# LEF of the project cell library pl018 (generated by step5_library/gen_library.py)
# Technology section copied from Qflow tech/osu018/osu018_stdcells.lef (layers, vias, via rules).
# The project library adds its own placement site and cell macros (step5_library/gen_library.py).
VERSION 5.4 ;
NAMESCASESENSITIVE ON ;
BUSBITCHARS "[]" ;
DIVIDERCHAR "/" ;
UNITS
  DATABASE MICRONS 1000 ;
END UNITS

USEMINSPACING OBS ON ;
USEMINSPACING PIN OFF ;
CLEARANCEMEASURE EUCLIDEAN ;


MANUFACTURINGGRID 0.05 ;

LAYER nwell
  TYPE	MASTERSLICE ;
END nwell

LAYER nactive
  TYPE	MASTERSLICE ;
END nactive

LAYER pactive
  TYPE	MASTERSLICE ;
END pactive

LAYER poly
  TYPE	MASTERSLICE ;
END poly

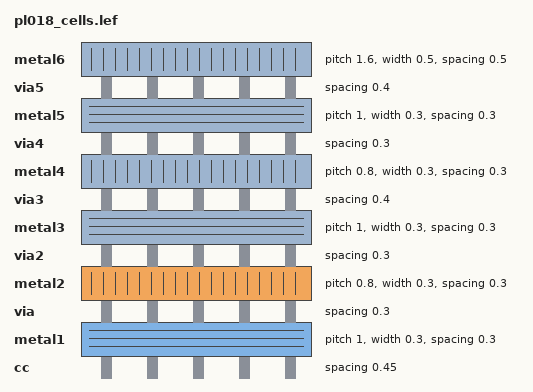
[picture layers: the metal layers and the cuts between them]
LAYER cc
  TYPE	CUT ;
  SPACING	0.45 ;
END cc

LAYER metal1
  TYPE		ROUTING ;
  DIRECTION	HORIZONTAL ;
  PITCH		1  ;
  OFFSET	0.5 ;
  WIDTH		0.3 ;
  SPACING	0.3 ;
  RESISTANCE	RPERSQ 0.08 ;
  CAPACITANCE	CPERSQDIST 3.8e-05 ;
  EDGECAPACITANCE 8.000000e-05 ;
END metal1

LAYER via
  TYPE	CUT ;
  SPACING	0.3 ;
END via

LAYER metal2
  TYPE		ROUTING ;
  DIRECTION	VERTICAL ;
  PITCH		0.8  ;
  OFFSET	0.4 ;
  WIDTH		0.3 ;
  SPACING	0.3 ;
  RESISTANCE	RPERSQ 0.08 ;
  CAPACITANCE	CPERSQDIST 1.9e-05 ;
  EDGECAPACITANCE 6.000000e-05 ;
END metal2

LAYER via2
  TYPE	CUT ;
  SPACING	0.3 ;
END via2

LAYER metal3
  TYPE		ROUTING ;
  DIRECTION	HORIZONTAL ;
  PITCH		1  ;
  OFFSET	0.5 ;
  WIDTH		0.3 ;
  SPACING	0.3 ;
  RESISTANCE	RPERSQ 0.08 ;
  CAPACITANCE	CPERSQDIST 1.3e-05 ;
  EDGECAPACITANCE 5.400000e-05 ;
END metal3

LAYER via3
  TYPE	CUT ;
  SPACING	0.4 ;
END via3

LAYER metal4
  TYPE		ROUTING ;
  DIRECTION	VERTICAL ;
  PITCH		0.8  ;
  OFFSET	0.4 ;
  WIDTH		0.3 ;
  SPACING	0.3 ;
  RESISTANCE	RPERSQ 0.07 ;
  CAPACITANCE	CPERSQDIST 8e-06 ;
  EDGECAPACITANCE 4.100000e-05 ;
END metal4

LAYER via4
  TYPE	CUT ;
  SPACING	0.3 ;
END via4

LAYER metal5
  TYPE		ROUTING ;
  DIRECTION	HORIZONTAL ;
  PITCH		1  ;
  OFFSET	0.5 ;
  WIDTH		0.3 ;
  SPACING	0.3 ;
  RESISTANCE	RPERSQ 0.07 ;
  CAPACITANCE	CPERSQDIST 8e-06 ;
  EDGECAPACITANCE 2.400000e-05 ;
END metal5

LAYER via5
  TYPE	CUT ;
  SPACING	0.4 ;
END via5

LAYER metal6
  TYPE		ROUTING ;
  DIRECTION	VERTICAL ;
  PITCH		1.6  ;
  OFFSET	0.8 ;
  WIDTH		0.5 ;
  SPACING	0.5 ;
  RESISTANCE	RPERSQ 0.03 ;
  CAPACITANCE	CPERSQDIST 3e-06 ;
  EDGECAPACITANCE 2.000000e-05 ;
END metal6

VIA M2_M1 DEFAULT
  LAYER metal1 ;
    RECT -0.200 -0.200 0.200 0.200 ;
  LAYER via ;
    RECT -0.100 -0.100 0.100 0.100 ;
  LAYER metal2 ;
    RECT -0.200 -0.200 0.200 0.200 ;
END M2_M1

VIA M3_M2 DEFAULT
  LAYER metal2 ;
    RECT -0.200 -0.200 0.200 0.200 ;
  LAYER via2 ;
    RECT -0.100 -0.100 0.100 0.100 ;
  LAYER metal3 ;
    RECT -0.200 -0.200 0.200 0.200 ;
END M3_M2

VIA M4_M3 DEFAULT
  LAYER metal3 ;
    RECT -0.200 -0.200 0.200 0.200 ;
  LAYER via3 ;
    RECT -0.100 -0.100 0.100 0.100 ;
  LAYER metal4 ;
    RECT -0.200 -0.200 0.200 0.200 ;
END M4_M3

VIA M5_M4 DEFAULT
  LAYER metal4 ;
    RECT -0.200 -0.200 0.200 0.200 ;
  LAYER via4 ;
    RECT -0.100 -0.100 0.100 0.100 ;
  LAYER metal5 ;
    RECT -0.200 -0.200 0.200 0.200 ;
END M5_M4

VIA M6_M5 DEFAULT
  LAYER metal5 ;
    RECT -0.25 -0.25 0.25 0.25 ;
  LAYER via5 ;
    RECT -0.15 -0.15 0.15 0.15 ;
  LAYER metal6 ;
    RECT -0.25 -0.25 0.25 0.25 ;
END M6_M5


VIARULE viagen21 GENERATE
  LAYER metal1 ;
    DIRECTION HORIZONTAL ;
    WIDTH 0.3 TO 60 ;
    OVERHANG 0.1 ;
    METALOVERHANG 0 ;
  LAYER metal2 ;
    DIRECTION VERTICAL ;
    WIDTH 0.3 TO 60 ;
    OVERHANG 0.1 ;
    METALOVERHANG 0 ;
  LAYER via ;
    RECT -0.1 -0.1 0.1 0.1 ;
    SPACING 0.5 BY 0.5 ;
END viagen21

VIARULE viagen32 GENERATE
  LAYER metal3 ;
    DIRECTION HORIZONTAL ;
    WIDTH 0.3 TO 60 ;
    OVERHANG 0.1 ;
    METALOVERHANG 0 ;
  LAYER metal2 ;
    DIRECTION VERTICAL ;
    WIDTH 0.3 TO 60 ;
    OVERHANG 0.1 ;
    METALOVERHANG 0 ;
  LAYER via2 ;
    RECT -0.1 -0.1 0.1 0.1 ;
    SPACING 0.5 BY 0.5 ;
END viagen32

VIARULE viagen43 GENERATE
  LAYER metal3 ;
    DIRECTION HORIZONTAL ;
    WIDTH 0.3 TO 60 ;
    OVERHANG 0.1 ;
    METALOVERHANG 0 ;
  LAYER metal4 ;
    DIRECTION VERTICAL ;
    WIDTH 0.3 TO 60 ;
    OVERHANG 0.1 ;
    METALOVERHANG 0 ;
  LAYER via3 ;
    RECT -0.1 -0.1 0.1 0.1 ;
    SPACING 0.6 BY 0.6 ;
END viagen43

VIARULE viagen54 GENERATE
  LAYER metal5 ;
    DIRECTION HORIZONTAL ;
    WIDTH 0.3 TO 60 ;
    OVERHANG 0.1 ;
    METALOVERHANG 0 ;
  LAYER metal4 ;
    DIRECTION VERTICAL ;
    WIDTH 0.3 TO 60 ;
    OVERHANG 0.1 ;
    METALOVERHANG 0 ;
  LAYER via4 ;
    RECT -0.1 -0.1 0.1 0.1 ;
    SPACING 0.5 BY 0.5 ;
END viagen54

VIARULE viagen65 GENERATE
  LAYER metal5 ;
    DIRECTION HORIZONTAL ;
    WIDTH 0.5 TO 60 ;
    OVERHANG 0.1 ;
    METALOVERHANG 0 ;
  LAYER metal6 ;
    DIRECTION VERTICAL ;
    WIDTH 0.5 TO 60 ;
    OVERHANG 0.1 ;
    METALOVERHANG 0 ;
  LAYER via5 ;
    RECT -0.15 -0.15 0.15 0.15 ;
    SPACING 0.7 BY 0.7 ;
END viagen65

VIARULE TURN1 GENERATE
  LAYER metal1 ;
    DIRECTION HORIZONTAL ;
  LAYER metal1 ;
    DIRECTION VERTICAL ;
END TURN1

VIARULE TURN2 GENERATE
  LAYER metal2 ;
    DIRECTION HORIZONTAL ;
  LAYER metal2 ;
    DIRECTION VERTICAL ;
END TURN2

VIARULE TURN3 GENERATE
  LAYER metal3 ;
    DIRECTION HORIZONTAL ;
  LAYER metal3 ;
    DIRECTION VERTICAL ;
END TURN3

VIARULE TURN4 GENERATE
  LAYER metal4 ;
    DIRECTION HORIZONTAL ;
  LAYER metal4 ;
    DIRECTION VERTICAL ;
END TURN4

VIARULE TURN5 GENERATE
  LAYER metal5 ;
    DIRECTION HORIZONTAL ;
  LAYER metal5 ;
    DIRECTION VERTICAL ;
END TURN5

VIARULE TURN6 GENERATE
  LAYER metal6 ;
    DIRECTION HORIZONTAL ;
  LAYER metal6 ;
    DIRECTION VERTICAL ;
END TURN6


SITE  plcore
    CLASS	CORE ;
    SYMMETRY	Y ;
    SIZE	0.800 BY 8.000 ;
END  plcore

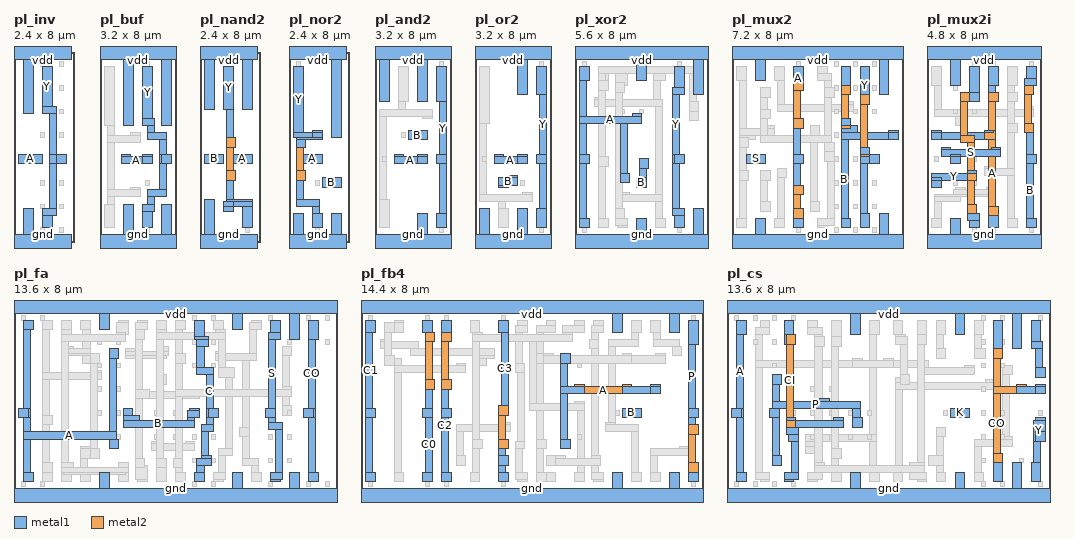
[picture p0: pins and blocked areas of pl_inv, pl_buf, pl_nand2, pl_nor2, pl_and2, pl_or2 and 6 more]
MACRO pl_inv
  CLASS CORE ;
  FOREIGN pl_inv 0.000 0.000 ;
  ORIGIN 0.000 0.000 ;
  SIZE 2.400 BY 8.000 ;
  SYMMETRY X Y ;
  SITE plcore ;
  PIN A
    DIRECTION INPUT ;
    PORT
      LAYER metal1 ;
        RECT 0.200 3.300 0.600 3.700 ;
        RECT 0.200 3.300 1.200 3.700 ;
    END
  END A
  PIN Y
    DIRECTION OUTPUT ;
    PORT
      LAYER metal1 ;
        RECT 1.800 3.300 2.200 3.700 ;
        RECT 1.200 0.600 1.600 1.100 ;
        RECT 1.200 1.100 1.800 1.400 ;
        RECT 1.500 1.400 1.800 3.300 ;
        RECT 1.500 3.300 2.200 3.700 ;
        RECT 1.500 3.700 1.800 5.400 ;
        RECT 1.200 5.400 1.800 5.700 ;
        RECT 1.200 5.700 1.600 7.400 ;
    END
  END Y
  PIN vdd
    DIRECTION INOUT ;
    USE POWER ;
    SHAPE ABUTMENT ;
    PORT
      LAYER metal1 ;
        RECT 0.400 5.400 0.800 7.700 ;
        RECT 0.000 7.700 2.400 8.300 ;
    END
  END vdd
  PIN gnd
    DIRECTION INOUT ;
    USE GROUND ;
    SHAPE ABUTMENT ;
    PORT
      LAYER metal1 ;
        RECT 0.000 -0.300 2.400 0.300 ;
        RECT 0.400 0.300 0.800 1.400 ;
    END
  END gnd
  OBS
    LAYER metal1 ;
      RECT 1.100 0.400 1.300 0.600 ;
      RECT 1.100 1.400 1.300 1.600 ;
      RECT 1.100 2.400 1.300 2.600 ;
      RECT 1.100 4.400 1.300 4.600 ;
      RECT 1.100 7.400 1.300 7.600 ;
      RECT 1.900 0.400 2.100 0.600 ;
      RECT 1.900 1.400 2.100 1.600 ;
      RECT 1.900 2.400 2.100 2.600 ;
      RECT 1.900 4.400 2.100 4.600 ;
      RECT 1.900 5.400 2.100 5.600 ;
      RECT 1.900 6.400 2.100 6.600 ;
      RECT 1.900 7.400 2.100 7.600 ;
  END
END pl_inv

MACRO pl_buf
  CLASS CORE ;
  FOREIGN pl_buf 0.000 0.000 ;
  ORIGIN 0.000 0.000 ;
  SIZE 3.200 BY 8.000 ;
  SYMMETRY X Y ;
  SITE plcore ;
  PIN A
    DIRECTION INPUT ;
    PORT
      LAYER metal1 ;
        RECT 1.800 3.300 2.200 3.700 ;
        RECT 0.900 3.300 2.200 3.600 ;
        RECT 0.900 3.600 1.300 3.700 ;
        RECT 1.800 3.600 2.200 3.700 ;
    END
  END A
  PIN Y
    DIRECTION OUTPUT ;
    PORT
      LAYER metal1 ;
        RECT 2.600 3.300 3.000 3.700 ;
        RECT 1.800 0.600 2.200 1.300 ;
        RECT 1.800 1.300 2.300 1.600 ;
        RECT 2.000 1.600 2.300 1.900 ;
        RECT 2.000 1.900 2.800 2.200 ;
        RECT 2.500 2.200 2.800 3.300 ;
        RECT 2.500 3.300 3.000 3.700 ;
        RECT 2.500 3.700 2.800 4.300 ;
        RECT 2.000 4.300 2.800 4.600 ;
        RECT 2.000 4.600 2.300 4.900 ;
        RECT 1.800 4.900 2.300 5.200 ;
        RECT 1.800 5.200 2.200 7.400 ;
    END
  END Y
  PIN vdd
    DIRECTION INOUT ;
    USE POWER ;
    SHAPE ABUTMENT ;
    PORT
      LAYER metal1 ;
        RECT 1.000 4.900 1.400 7.700 ;
        RECT 2.600 4.900 3.000 7.700 ;
        RECT 0.000 7.700 3.200 8.300 ;
    END
  END vdd
  PIN gnd
    DIRECTION INOUT ;
    USE GROUND ;
    SHAPE ABUTMENT ;
    PORT
      LAYER metal1 ;
        RECT 0.000 -0.300 3.200 0.300 ;
        RECT 1.000 0.300 1.400 1.600 ;
        RECT 2.600 0.300 3.000 1.600 ;
    END
  END gnd
  OBS
    LAYER metal1 ;
      RECT 0.200 0.600 0.600 1.600 ;
      RECT 0.300 1.600 0.600 1.900 ;
      RECT 0.300 1.900 1.700 2.200 ;
      RECT 0.300 2.200 0.600 4.200 ;
      RECT 1.300 2.200 1.700 2.300 ;
      RECT 0.300 4.200 1.700 4.500 ;
      RECT 0.300 4.500 0.600 4.900 ;
      RECT 1.300 4.500 1.700 4.600 ;
      RECT 0.200 4.900 0.600 7.400 ;
      RECT 1.900 0.400 2.100 0.600 ;
      RECT 1.900 2.400 2.100 2.600 ;
      RECT 1.900 7.400 2.100 7.600 ;
  END
END pl_buf

MACRO pl_nand2
  CLASS CORE ;
  FOREIGN pl_nand2 0.000 0.000 ;
  ORIGIN 0.000 0.000 ;
  SIZE 2.400 BY 8.000 ;
  SYMMETRY X Y ;
  SITE plcore ;
  PIN A
    DIRECTION INPUT ;
    PORT
      LAYER metal1 ;
        RECT 1.800 3.300 2.200 3.700 ;
        RECT 1.400 3.300 2.200 3.700 ;
    END
  END A
  PIN B
    DIRECTION INPUT ;
    PORT
      LAYER metal1 ;
        RECT 0.200 3.300 0.600 3.700 ;
        RECT 0.200 3.300 1.000 3.700 ;
    END
  END B
  PIN Y
    DIRECTION OUTPUT ;
    PORT
      LAYER metal1 ;
        RECT 1.000 1.300 1.400 1.700 ;
        RECT 1.800 0.600 2.200 1.500 ;
        RECT 1.000 1.300 1.400 1.500 ;
        RECT 1.000 1.500 2.200 1.700 ;
        RECT 1.100 1.700 2.200 1.800 ;
        RECT 1.100 1.800 1.400 2.600 ;
        RECT 1.100 2.600 1.500 3.000 ;
        RECT 1.100 4.000 1.500 4.400 ;
        RECT 1.100 4.400 1.400 5.600 ;
        RECT 1.000 5.600 1.400 7.400 ;
      LAYER metal2 ;
        RECT 1.100 2.600 1.500 3.000 ;
        RECT 1.100 3.000 1.400 4.000 ;
        RECT 1.100 4.000 1.500 4.400 ;
    END
  END Y
  PIN vdd
    DIRECTION INOUT ;
    USE POWER ;
    SHAPE ABUTMENT ;
    PORT
      LAYER metal1 ;
        RECT 0.200 5.600 0.600 7.700 ;
        RECT 1.800 5.600 2.200 7.700 ;
        RECT 0.000 7.700 2.400 8.300 ;
    END
  END vdd
  PIN gnd
    DIRECTION INOUT ;
    USE GROUND ;
    SHAPE ABUTMENT ;
    PORT
      LAYER metal1 ;
        RECT 0.000 -0.300 2.400 0.300 ;
        RECT 0.200 0.300 0.600 1.800 ;
    END
  END gnd
  OBS
    LAYER metal1 ;
      RECT 1.100 3.400 1.300 3.600 ;
      RECT 1.100 7.400 1.300 7.600 ;
      RECT 1.900 0.400 2.100 0.600 ;
  END
END pl_nand2

MACRO pl_nor2
  CLASS CORE ;
  FOREIGN pl_nor2 0.000 0.000 ;
  ORIGIN 0.000 0.000 ;
  SIZE 2.400 BY 8.000 ;
  SYMMETRY X Y ;
  SITE plcore ;
  PIN A
    DIRECTION INPUT ;
    PORT
      LAYER metal1 ;
        RECT 1.000 3.300 1.400 3.700 ;
        RECT 0.600 3.300 1.400 3.700 ;
    END
  END A
  PIN B
    DIRECTION INPUT ;
    PORT
      LAYER metal1 ;
        RECT 1.800 2.300 2.200 2.700 ;
        RECT 1.400 2.300 2.200 2.700 ;
    END
  END B
  PIN Y
    DIRECTION OUTPUT ;
    PORT
      LAYER metal1 ;
        RECT 1.000 4.300 1.400 4.700 ;
        RECT 1.000 0.600 1.400 1.200 ;
        RECT 1.000 1.200 1.300 1.500 ;
        RECT 0.300 1.500 1.300 1.800 ;
        RECT 0.300 1.800 0.600 2.600 ;
        RECT 0.300 2.600 0.700 3.000 ;
        RECT 0.300 4.000 0.700 4.300 ;
        RECT 0.300 4.300 1.400 4.400 ;
        RECT 0.200 4.400 1.400 4.600 ;
        RECT 0.200 4.600 0.600 7.400 ;
        RECT 1.000 4.600 1.400 4.700 ;
      LAYER metal2 ;
        RECT 0.300 2.600 0.700 3.000 ;
        RECT 0.300 3.000 0.600 4.000 ;
        RECT 0.300 4.000 0.700 4.400 ;
    END
  END Y
  PIN vdd
    DIRECTION INOUT ;
    USE POWER ;
    SHAPE ABUTMENT ;
    PORT
      LAYER metal1 ;
        RECT 1.800 4.400 2.200 7.700 ;
        RECT 0.000 7.700 2.400 8.300 ;
    END
  END vdd
  PIN gnd
    DIRECTION INOUT ;
    USE GROUND ;
    SHAPE ABUTMENT ;
    PORT
      LAYER metal1 ;
        RECT 0.000 -0.300 2.400 0.300 ;
        RECT 0.200 0.300 0.600 1.200 ;
        RECT 1.800 0.300 2.200 1.200 ;
    END
  END gnd
  OBS
    LAYER metal1 ;
      RECT 0.300 3.400 0.500 3.600 ;
      RECT 0.300 7.400 0.500 7.600 ;
      RECT 1.100 0.400 1.300 0.600 ;
      RECT 1.100 2.400 1.300 2.600 ;
    LAYER metal2 ;
      RECT 0.300 2.400 0.500 2.600 ;
      RECT 0.300 4.400 0.500 4.600 ;
  END
END pl_nor2

MACRO pl_and2
  CLASS CORE ;
  FOREIGN pl_and2 0.000 0.000 ;
  ORIGIN 0.000 0.000 ;
  SIZE 3.200 BY 8.000 ;
  SYMMETRY X Y ;
  SITE plcore ;
  PIN A
    DIRECTION INPUT ;
    PORT
      LAYER metal1 ;
        RECT 1.800 3.300 2.200 3.700 ;
        RECT 0.800 3.300 2.200 3.600 ;
        RECT 0.800 3.600 1.200 3.700 ;
        RECT 1.800 3.600 2.200 3.700 ;
    END
  END A
  PIN B
    DIRECTION INPUT ;
    PORT
      LAYER metal1 ;
        RECT 1.800 4.300 2.200 4.700 ;
        RECT 1.400 4.300 2.200 4.700 ;
    END
  END B
  PIN Y
    DIRECTION OUTPUT ;
    PORT
      LAYER metal1 ;
        RECT 2.600 3.300 3.000 3.700 ;
        RECT 2.600 0.600 3.000 1.200 ;
        RECT 2.700 1.200 3.000 3.300 ;
        RECT 2.600 3.300 3.000 3.700 ;
        RECT 2.700 3.700 3.000 5.900 ;
        RECT 2.600 5.900 3.000 7.400 ;
    END
  END Y
  PIN vdd
    DIRECTION INOUT ;
    USE POWER ;
    SHAPE ABUTMENT ;
    PORT
      LAYER metal1 ;
        RECT 0.200 5.900 0.600 7.700 ;
        RECT 1.800 5.900 2.200 7.700 ;
        RECT 0.000 7.700 3.200 8.300 ;
    END
  END vdd
  PIN gnd
    DIRECTION INOUT ;
    USE GROUND ;
    SHAPE ABUTMENT ;
    PORT
      LAYER metal1 ;
        RECT 0.000 -0.300 3.200 0.300 ;
        RECT 1.800 0.300 2.200 1.200 ;
    END
  END gnd
  OBS
    LAYER metal1 ;
      RECT 0.200 0.600 0.600 1.800 ;
      RECT 0.200 1.800 0.500 5.300 ;
      RECT 2.000 5.200 2.400 5.300 ;
      RECT 0.200 5.300 2.400 5.600 ;
      RECT 1.000 5.600 1.300 5.900 ;
      RECT 1.000 5.900 1.400 7.400 ;
      RECT 0.300 3.400 0.500 3.600 ;
      RECT 1.100 4.400 1.300 4.600 ;
      RECT 2.700 0.400 2.900 0.600 ;
      RECT 2.700 7.400 2.900 7.600 ;
  END
END pl_and2

MACRO pl_or2
  CLASS CORE ;
  FOREIGN pl_or2 0.000 0.000 ;
  ORIGIN 0.000 0.000 ;
  SIZE 3.200 BY 8.000 ;
  SYMMETRY X Y ;
  SITE plcore ;
  PIN A
    DIRECTION INPUT ;
    PORT
      LAYER metal1 ;
        RECT 1.800 3.300 2.200 3.700 ;
        RECT 0.800 3.300 2.200 3.600 ;
        RECT 0.800 3.600 1.200 3.700 ;
        RECT 1.800 3.600 2.200 3.700 ;
    END
  END A
  PIN B
    DIRECTION INPUT ;
    PORT
      LAYER metal1 ;
        RECT 1.000 2.300 1.400 2.700 ;
        RECT 1.000 2.300 1.400 2.400 ;
        RECT 1.000 2.400 1.800 2.700 ;
        RECT 1.400 2.700 1.800 2.800 ;
    END
  END B
  PIN Y
    DIRECTION OUTPUT ;
    PORT
      LAYER metal1 ;
        RECT 2.600 3.300 3.000 3.700 ;
        RECT 2.600 0.600 3.000 1.400 ;
        RECT 2.700 1.400 3.000 3.300 ;
        RECT 2.600 3.300 3.000 3.700 ;
        RECT 2.700 3.700 3.000 6.200 ;
        RECT 2.600 6.200 3.000 7.400 ;
    END
  END Y
  PIN vdd
    DIRECTION INOUT ;
    USE POWER ;
    SHAPE ABUTMENT ;
    PORT
      LAYER metal1 ;
        RECT 1.800 6.200 2.200 7.700 ;
        RECT 0.000 7.700 3.200 8.300 ;
    END
  END vdd
  PIN gnd
    DIRECTION INOUT ;
    USE GROUND ;
    SHAPE ABUTMENT ;
    PORT
      LAYER metal1 ;
        RECT 0.000 -0.300 3.200 0.300 ;
        RECT 0.200 0.300 0.600 1.400 ;
        RECT 1.800 0.300 2.200 1.400 ;
    END
  END gnd
  OBS
    LAYER metal1 ;
      RECT 1.000 0.600 1.400 1.400 ;
      RECT 1.000 1.400 1.300 1.700 ;
      RECT 0.200 1.700 2.400 2.000 ;
      RECT 0.200 2.000 0.500 5.000 ;
      RECT 2.000 2.000 2.400 2.100 ;
      RECT 0.200 5.000 0.600 7.400 ;
      RECT 0.300 3.400 0.500 3.600 ;
      RECT 1.900 2.400 2.100 2.600 ;
      RECT 2.700 0.400 2.900 0.600 ;
      RECT 2.700 7.400 2.900 7.600 ;
  END
END pl_or2

MACRO pl_xor2
  CLASS CORE ;
  FOREIGN pl_xor2 0.000 0.000 ;
  ORIGIN 0.000 0.000 ;
  SIZE 5.600 BY 8.000 ;
  SYMMETRY X Y ;
  SITE plcore ;
  PIN A
    DIRECTION INPUT ;
    PORT
      LAYER metal1 ;
        RECT 0.200 3.300 0.600 3.700 ;
        RECT 0.200 0.600 0.600 1.000 ;
        RECT 0.200 1.000 0.500 3.300 ;
        RECT 1.900 2.500 2.300 2.900 ;
        RECT 1.900 2.900 2.200 5.000 ;
        RECT 0.200 3.300 0.600 3.700 ;
        RECT 0.200 3.700 0.500 5.000 ;
        RECT 0.200 5.000 2.800 5.300 ;
        RECT 0.200 5.300 0.500 6.800 ;
        RECT 2.400 5.300 2.800 5.400 ;
        RECT 0.200 6.800 0.600 7.400 ;
    END
  END A
  PIN B
    DIRECTION INPUT ;
    PORT
      LAYER metal1 ;
        RECT 2.600 2.300 3.000 2.700 ;
        RECT 2.600 2.300 3.000 2.700 ;
        RECT 2.700 2.700 3.000 3.100 ;
        RECT 2.700 3.100 3.100 3.500 ;
    END
  END B
  PIN Y
    DIRECTION OUTPUT ;
    PORT
      LAYER metal1 ;
        RECT 4.200 3.300 4.600 3.700 ;
        RECT 4.200 0.600 4.600 1.100 ;
        RECT 4.100 1.100 4.600 1.400 ;
        RECT 4.100 1.400 4.400 3.300 ;
        RECT 4.100 3.300 4.600 3.700 ;
        RECT 4.100 3.700 4.400 6.200 ;
        RECT 4.100 6.200 4.600 6.500 ;
        RECT 4.200 6.500 4.600 7.400 ;
    END
  END Y
  PIN vdd
    DIRECTION INOUT ;
    USE POWER ;
    SHAPE ABUTMENT ;
    PORT
      LAYER metal1 ;
        RECT 5.000 6.200 5.400 7.700 ;
        RECT 2.600 6.800 3.000 7.700 ;
        RECT 0.000 7.700 5.600 8.300 ;
    END
  END vdd
  PIN gnd
    DIRECTION INOUT ;
    USE GROUND ;
    SHAPE ABUTMENT ;
    PORT
      LAYER metal1 ;
        RECT 0.000 -0.300 5.600 0.300 ;
        RECT 2.600 0.300 3.000 1.000 ;
        RECT 5.000 0.300 5.400 1.400 ;
    END
  END gnd
  OBS
    LAYER metal1 ;
      RECT 1.000 0.600 1.400 1.000 ;
      RECT 1.800 0.600 2.200 0.700 ;
      RECT 3.400 0.600 3.800 1.000 ;
      RECT 1.700 0.700 2.200 1.000 ;
      RECT 1.000 1.000 1.300 3.200 ;
      RECT 1.700 1.000 2.100 1.400 ;
      RECT 3.400 1.000 3.700 1.700 ;
      RECT 1.900 1.700 3.700 2.000 ;
      RECT 1.900 2.000 2.300 2.100 ;
      RECT 3.400 2.000 3.700 5.700 ;
      RECT 1.000 3.200 1.400 3.600 ;
      RECT 4.800 5.100 5.200 5.900 ;
      RECT 0.800 5.700 3.700 6.000 ;
      RECT 0.800 6.000 1.200 6.100 ;
      RECT 3.300 6.000 3.600 6.800 ;
      RECT 1.700 6.300 2.100 6.600 ;
      RECT 1.000 6.400 1.400 7.400 ;
      RECT 1.700 6.600 2.200 7.100 ;
      RECT 3.300 6.800 3.800 7.100 ;
      RECT 1.800 7.100 2.200 7.400 ;
      RECT 3.400 7.100 3.800 7.400 ;
      RECT 0.300 0.400 0.500 0.600 ;
      RECT 0.300 7.400 0.500 7.600 ;
      RECT 1.100 5.400 1.300 5.600 ;
      RECT 1.900 5.400 2.100 5.600 ;
      RECT 2.700 5.400 2.900 5.600 ;
      RECT 4.300 0.400 4.500 0.600 ;
      RECT 4.300 7.400 4.500 7.600 ;
    LAYER metal2 ;
      RECT 1.700 1.000 2.100 1.400 ;
      RECT 1.700 1.400 2.000 6.300 ;
      RECT 1.000 3.200 1.400 3.600 ;
      RECT 1.000 3.600 1.300 6.400 ;
      RECT 4.800 5.500 5.200 5.900 ;
      RECT 4.800 5.900 5.100 7.100 ;
      RECT 1.700 6.300 2.100 6.700 ;
      RECT 1.000 6.400 1.400 6.800 ;
      RECT 1.000 6.800 1.300 7.100 ;
      RECT 1.000 7.100 5.100 7.400 ;
  END
END pl_xor2

MACRO pl_mux2
  CLASS CORE ;
  FOREIGN pl_mux2 0.000 0.000 ;
  ORIGIN 0.000 0.000 ;
  SIZE 7.200 BY 8.000 ;
  SYMMETRY X Y ;
  SITE plcore ;
  PIN A
    DIRECTION INPUT ;
    PORT
      LAYER metal1 ;
        RECT 2.600 3.300 3.000 3.700 ;
        RECT 2.600 0.600 3.000 1.400 ;
        RECT 2.600 2.000 3.000 2.400 ;
        RECT 2.600 2.400 2.900 3.300 ;
        RECT 2.600 3.300 3.000 3.700 ;
        RECT 2.600 3.700 2.900 4.800 ;
        RECT 2.600 4.800 3.000 5.200 ;
        RECT 2.600 6.400 3.000 7.400 ;
      LAYER metal2 ;
        RECT 2.600 1.000 3.000 1.400 ;
        RECT 2.600 1.400 2.900 2.000 ;
        RECT 2.600 2.000 3.000 2.400 ;
        RECT 2.600 4.800 3.000 5.200 ;
        RECT 2.600 5.200 2.900 6.400 ;
        RECT 2.600 6.400 3.000 6.800 ;
    END
  END A
  PIN B
    DIRECTION INPUT ;
    PORT
      LAYER metal1 ;
        RECT 6.600 4.300 7.000 4.700 ;
        RECT 4.600 0.600 5.000 1.000 ;
        RECT 4.600 1.000 4.900 4.300 ;
        RECT 4.600 4.300 7.000 4.600 ;
        RECT 4.600 4.600 5.300 4.900 ;
        RECT 6.600 4.600 7.000 4.700 ;
        RECT 4.600 4.900 5.000 5.200 ;
        RECT 4.600 6.200 5.000 7.400 ;
      LAYER metal2 ;
        RECT 4.600 4.800 5.000 5.200 ;
        RECT 4.600 5.200 4.900 6.200 ;
        RECT 4.600 6.200 5.000 6.600 ;
    END
  END B
  PIN S
    DIRECTION INPUT ;
    PORT
      LAYER metal1 ;
        RECT 1.000 3.300 1.400 3.700 ;
        RECT 0.600 3.300 1.400 3.700 ;
    END
  END S
  PIN Y
    DIRECTION OUTPUT ;
    PORT
      LAYER metal1 ;
        RECT 5.800 3.300 6.200 3.700 ;
        RECT 5.400 0.600 5.800 1.200 ;
        RECT 5.400 1.200 5.700 3.300 ;
        RECT 5.400 3.300 6.200 3.700 ;
        RECT 5.400 3.700 5.800 4.000 ;
        RECT 5.400 5.800 5.800 7.400 ;
      LAYER metal2 ;
        RECT 5.400 3.600 5.800 4.000 ;
        RECT 5.400 4.000 5.700 5.800 ;
        RECT 5.400 5.800 5.800 6.200 ;
    END
  END Y
  PIN vdd
    DIRECTION INOUT ;
    USE POWER ;
    SHAPE ABUTMENT ;
    PORT
      LAYER metal1 ;
        RECT 6.200 6.200 6.600 7.700 ;
        RECT 1.000 6.800 1.400 7.700 ;
        RECT 0.000 7.700 7.200 8.300 ;
    END
  END vdd
  PIN gnd
    DIRECTION INOUT ;
    USE GROUND ;
    SHAPE ABUTMENT ;
    PORT
      LAYER metal1 ;
        RECT 0.000 -0.300 7.200 0.300 ;
        RECT 1.000 0.300 1.400 1.000 ;
        RECT 6.200 0.300 6.600 1.200 ;
    END
  END gnd
  OBS
    LAYER metal1 ;
      RECT 0.200 0.600 0.600 1.000 ;
      RECT 1.800 0.600 2.200 1.000 ;
      RECT 3.600 0.600 4.000 0.700 ;
      RECT 3.600 0.700 4.300 1.000 ;
      RECT 0.300 1.000 0.600 2.600 ;
      RECT 1.900 1.000 2.200 2.700 ;
      RECT 4.000 1.000 4.300 3.400 ;
      RECT 1.200 1.300 1.600 1.700 ;
      RECT 3.300 1.300 3.700 1.700 ;
      RECT 1.200 1.700 1.500 2.600 ;
      RECT 3.300 1.700 3.600 4.500 ;
      RECT 0.300 2.600 0.700 3.000 ;
      RECT 1.200 2.600 1.600 3.000 ;
      RECT 1.900 2.700 2.300 3.100 ;
      RECT 3.900 3.400 4.300 4.200 ;
      RECT 0.300 4.000 0.700 4.300 ;
      RECT 0.300 4.300 1.000 4.500 ;
      RECT 0.300 4.500 1.800 4.800 ;
      RECT 3.300 4.500 3.700 4.900 ;
      RECT 0.300 4.800 0.600 6.800 ;
      RECT 1.400 4.800 1.800 4.900 ;
      RECT 1.200 5.200 1.600 5.600 ;
      RECT 1.900 5.500 5.100 5.800 ;
      RECT 1.200 5.600 1.500 6.100 ;
      RECT 1.900 5.800 2.200 6.800 ;
      RECT 4.700 5.800 5.100 5.900 ;
      RECT 1.200 6.100 1.600 6.500 ;
      RECT 3.900 6.100 4.300 6.500 ;
      RECT 3.900 6.500 4.200 6.800 ;
      RECT 0.200 6.800 0.600 7.400 ;
      RECT 1.800 6.800 2.200 7.400 ;
      RECT 3.600 6.800 4.200 7.100 ;
      RECT 3.600 7.100 4.000 7.400 ;
      RECT 0.300 3.400 0.500 3.600 ;
      RECT 2.700 0.400 2.900 0.600 ;
      RECT 2.700 1.400 2.900 1.600 ;
      RECT 2.700 5.400 2.900 5.600 ;
      RECT 2.700 7.400 2.900 7.600 ;
      RECT 4.300 0.400 4.500 0.600 ;
      RECT 4.300 1.400 4.500 1.600 ;
      RECT 4.300 2.400 4.500 2.600 ;
      RECT 4.300 3.400 4.500 3.600 ;
      RECT 4.300 4.400 4.500 4.600 ;
      RECT 4.300 5.400 4.500 5.600 ;
      RECT 4.300 6.400 4.500 6.600 ;
      RECT 4.300 7.400 4.500 7.600 ;
      RECT 5.100 0.400 5.300 0.600 ;
      RECT 5.100 1.400 5.300 1.600 ;
      RECT 5.100 2.400 5.300 2.600 ;
      RECT 5.100 3.400 5.300 3.600 ;
      RECT 5.100 5.400 5.300 5.600 ;
      RECT 5.100 6.400 5.300 6.600 ;
      RECT 5.100 7.400 5.300 7.600 ;
      RECT 5.900 0.400 6.100 0.600 ;
      RECT 5.900 1.400 6.100 1.600 ;
      RECT 5.900 2.400 6.100 2.600 ;
      RECT 5.900 5.400 6.100 5.600 ;
      RECT 5.900 6.400 6.100 6.600 ;
      RECT 5.900 7.400 6.100 7.600 ;
    LAYER metal2 ;
      RECT 0.300 2.600 0.700 3.000 ;
      RECT 0.300 3.000 0.600 4.000 ;
      RECT 3.900 3.800 4.300 4.200 ;
      RECT 0.300 4.000 0.700 4.400 ;
      RECT 1.200 4.200 4.200 4.500 ;
      RECT 1.200 4.500 1.500 5.200 ;
      RECT 3.900 4.500 4.200 6.100 ;
      RECT 1.200 5.200 1.600 5.600 ;
      RECT 3.900 6.100 4.300 6.500 ;
      RECT 4.300 4.400 4.500 4.600 ;
      RECT 4.300 5.400 4.500 5.600 ;
      RECT 4.300 6.400 4.500 6.600 ;
      RECT 5.100 3.400 5.300 3.600 ;
      RECT 5.100 4.400 5.300 4.600 ;
      RECT 5.100 5.400 5.300 5.600 ;
      RECT 5.100 6.400 5.300 6.600 ;
  END
END pl_mux2

MACRO pl_mux2i
  CLASS CORE ;
  FOREIGN pl_mux2i 0.000 0.000 ;
  ORIGIN 0.000 0.000 ;
  SIZE 4.800 BY 8.000 ;
  SYMMETRY X Y ;
  SITE plcore ;
  PIN A
    DIRECTION INPUT ;
    PORT
      LAYER metal1 ;
        RECT 0.200 4.300 0.600 4.700 ;
        RECT 2.600 0.600 3.000 1.500 ;
        RECT 0.200 4.300 2.800 4.600 ;
        RECT 0.200 4.600 0.600 4.700 ;
        RECT 2.400 4.600 2.800 4.700 ;
        RECT 2.600 5.900 3.000 6.300 ;
        RECT 2.600 6.300 2.900 6.600 ;
        RECT 2.600 6.600 3.000 7.400 ;
      LAYER metal2 ;
        RECT 2.600 1.100 3.000 1.500 ;
        RECT 2.600 1.500 2.900 4.300 ;
        RECT 2.400 4.300 2.900 4.700 ;
        RECT 2.600 4.700 2.900 5.900 ;
        RECT 2.600 5.900 3.000 6.300 ;
    END
  END A
  PIN B
    DIRECTION INPUT ;
    PORT
      LAYER metal1 ;
        RECT 4.200 3.300 4.600 3.700 ;
        RECT 4.200 0.600 4.600 1.000 ;
        RECT 4.200 1.000 4.500 3.300 ;
        RECT 4.200 3.300 4.600 3.700 ;
        RECT 4.200 3.700 4.500 4.600 ;
        RECT 4.100 4.600 4.500 5.000 ;
        RECT 4.100 6.200 4.500 6.600 ;
        RECT 4.100 6.600 4.600 6.900 ;
        RECT 4.200 6.900 4.600 7.400 ;
      LAYER metal2 ;
        RECT 4.100 4.600 4.500 5.000 ;
        RECT 4.100 5.000 4.400 6.200 ;
        RECT 4.100 6.200 4.500 6.600 ;
    END
  END B
  PIN S
    DIRECTION INPUT ;
    PORT
      LAYER metal1 ;
        RECT 1.000 3.300 1.400 3.700 ;
        RECT 1.000 3.300 1.400 3.600 ;
        RECT 0.600 3.600 3.100 3.900 ;
        RECT 0.600 3.900 1.000 4.000 ;
        RECT 2.700 3.900 3.100 4.000 ;
    END
  END S
  PIN Y
    DIRECTION OUTPUT ;
    PORT
      LAYER metal1 ;
        RECT 0.200 2.300 0.600 2.700 ;
        RECT 1.800 0.600 2.200 0.900 ;
        RECT 1.700 0.900 2.200 1.200 ;
        RECT 1.700 1.200 2.100 1.600 ;
        RECT 0.200 2.300 0.600 2.600 ;
        RECT 0.200 2.600 2.100 2.900 ;
        RECT 1.700 2.900 2.100 3.000 ;
        RECT 1.400 5.900 2.200 6.300 ;
        RECT 1.800 6.300 2.200 7.400 ;
      LAYER metal2 ;
        RECT 1.700 1.200 2.100 1.600 ;
        RECT 1.700 1.600 2.000 2.600 ;
        RECT 1.700 2.600 2.100 3.000 ;
        RECT 1.700 3.000 2.000 4.200 ;
        RECT 1.400 4.200 2.000 4.500 ;
        RECT 1.400 4.500 1.700 5.900 ;
        RECT 1.400 5.900 1.800 6.300 ;
    END
  END Y
  PIN vdd
    DIRECTION INOUT ;
    USE POWER ;
    SHAPE ABUTMENT ;
    PORT
      LAYER metal1 ;
        RECT 1.000 6.600 1.400 7.700 ;
        RECT 0.000 7.700 4.800 8.300 ;
    END
  END vdd
  PIN gnd
    DIRECTION INOUT ;
    USE GROUND ;
    SHAPE ABUTMENT ;
    PORT
      LAYER metal1 ;
        RECT 0.000 -0.300 4.800 0.300 ;
        RECT 1.000 0.300 1.400 1.000 ;
    END
  END gnd
  OBS
    LAYER metal1 ;
      RECT 0.200 0.600 0.600 1.000 ;
      RECT 3.400 0.600 3.800 1.000 ;
      RECT 0.300 1.000 0.600 1.700 ;
      RECT 3.400 1.000 3.700 2.800 ;
      RECT 0.300 1.700 1.400 1.900 ;
      RECT 0.300 1.900 2.900 2.000 ;
      RECT 1.100 2.000 2.900 2.200 ;
      RECT 1.200 2.200 1.600 2.300 ;
      RECT 2.500 2.200 2.900 2.300 ;
      RECT 2.400 2.800 3.700 3.100 ;
      RECT 2.400 3.100 2.800 3.200 ;
      RECT 3.400 3.100 3.700 4.600 ;
      RECT 3.400 4.600 3.800 5.000 ;
      RECT 1.200 4.900 1.600 5.300 ;
      RECT 0.300 5.300 4.500 5.600 ;
      RECT 0.300 5.600 0.600 6.600 ;
      RECT 4.100 5.600 4.500 5.700 ;
      RECT 3.400 5.900 3.800 6.300 ;
      RECT 3.400 6.300 3.700 6.600 ;
      RECT 0.200 6.600 0.600 7.400 ;
      RECT 3.400 6.600 3.800 7.400 ;
      RECT 0.300 3.400 0.500 3.600 ;
      RECT 1.100 2.400 1.300 2.600 ;
      RECT 1.100 5.400 1.300 5.600 ;
      RECT 1.100 6.400 1.300 6.600 ;
      RECT 1.900 0.400 2.100 0.600 ;
      RECT 1.900 2.400 2.100 2.600 ;
      RECT 1.900 3.400 2.100 3.600 ;
      RECT 1.900 5.400 2.100 5.600 ;
      RECT 1.900 7.400 2.100 7.600 ;
      RECT 2.700 0.400 2.900 0.600 ;
      RECT 2.700 3.400 2.900 3.600 ;
      RECT 2.700 5.400 2.900 5.600 ;
      RECT 2.700 7.400 2.900 7.600 ;
      RECT 4.300 0.400 4.500 0.600 ;
      RECT 4.300 7.400 4.500 7.600 ;
    LAYER metal2 ;
      RECT 3.400 4.600 3.800 5.000 ;
      RECT 3.400 5.000 3.700 5.900 ;
      RECT 3.400 5.900 3.800 6.300 ;
      RECT 1.100 4.400 1.300 4.600 ;
      RECT 1.100 5.400 1.300 5.600 ;
      RECT 1.100 6.400 1.300 6.600 ;
      RECT 1.900 5.400 2.100 5.600 ;
      RECT 1.900 6.400 2.100 6.600 ;
      RECT 2.700 6.400 2.900 6.600 ;
  END
END pl_mux2i

MACRO pl_fa
  CLASS CORE ;
  FOREIGN pl_fa 0.000 0.000 ;
  ORIGIN 0.000 0.000 ;
  SIZE 13.600 BY 8.000 ;
  SYMMETRY X Y ;
  SITE plcore ;
  PIN A
    DIRECTION INPUT ;
    PORT
      LAYER metal1 ;
        RECT 0.200 3.300 0.600 3.700 ;
        RECT 0.400 0.600 0.800 1.000 ;
        RECT 0.400 1.000 0.700 2.400 ;
        RECT 4.000 2.000 4.400 2.400 ;
        RECT 0.400 2.400 4.300 2.700 ;
        RECT 0.400 2.700 0.700 3.300 ;
        RECT 4.000 2.700 4.300 5.800 ;
        RECT 0.200 3.300 0.700 3.700 ;
        RECT 0.400 3.700 0.700 7.000 ;
        RECT 4.000 5.800 4.400 6.200 ;
        RECT 0.400 7.000 0.800 7.400 ;
    END
  END A
  PIN B
    DIRECTION INPUT ;
    PORT
      LAYER metal1 ;
        RECT 7.400 3.300 7.800 3.700 ;
        RECT 4.600 2.900 7.600 3.200 ;
        RECT 4.600 3.200 5.300 3.400 ;
        RECT 7.300 3.200 7.600 3.300 ;
        RECT 7.300 3.300 7.800 3.600 ;
        RECT 4.600 3.400 5.000 3.700 ;
        RECT 7.400 3.600 7.800 3.700 ;
    END
  END B
  PIN C
    DIRECTION INPUT ;
    PORT
      LAYER metal1 ;
        RECT 8.200 3.300 8.600 3.700 ;
        RECT 7.600 0.600 8.000 1.000 ;
        RECT 7.700 1.000 8.000 1.300 ;
        RECT 7.700 1.300 8.300 1.600 ;
        RECT 7.900 1.600 8.300 1.700 ;
        RECT 7.900 1.700 8.200 2.700 ;
        RECT 7.900 2.700 8.400 3.000 ;
        RECT 8.100 3.000 8.400 3.300 ;
        RECT 8.100 3.300 8.600 3.700 ;
        RECT 8.100 3.700 8.400 5.100 ;
        RECT 7.700 5.100 8.400 5.400 ;
        RECT 7.700 5.400 8.000 6.300 ;
        RECT 7.700 6.300 8.200 6.600 ;
        RECT 7.600 6.600 8.200 6.700 ;
        RECT 7.600 6.700 8.000 7.400 ;
    END
  END C
  PIN S
    DIRECTION OUTPUT ;
    PORT
      LAYER metal1 ;
        RECT 10.600 3.300 11.000 3.700 ;
        RECT 10.800 0.600 11.200 0.700 ;
        RECT 10.800 0.700 11.300 1.000 ;
        RECT 11.000 1.000 11.300 2.800 ;
        RECT 10.700 2.800 11.300 3.100 ;
        RECT 10.700 3.100 11.000 3.300 ;
        RECT 10.600 3.300 11.000 3.700 ;
        RECT 10.700 3.700 11.000 6.600 ;
        RECT 10.700 6.600 11.200 6.900 ;
        RECT 10.800 6.900 11.200 7.400 ;
    END
  END S
  PIN CO
    DIRECTION OUTPUT ;
    PORT
      LAYER metal1 ;
        RECT 12.200 3.300 12.600 3.700 ;
        RECT 12.400 0.600 12.800 1.000 ;
        RECT 12.400 1.000 12.700 3.300 ;
        RECT 12.200 3.300 12.700 3.700 ;
        RECT 12.400 3.700 12.700 6.600 ;
        RECT 12.400 6.600 12.800 7.400 ;
    END
  END CO
  PIN vdd
    DIRECTION INOUT ;
    USE POWER ;
    SHAPE ABUTMENT ;
    PORT
      LAYER metal1 ;
        RECT 11.600 6.600 12.000 7.700 ;
        RECT 3.600 7.000 4.000 7.700 ;
        RECT 9.200 7.000 9.600 7.700 ;
        RECT 0.000 7.700 13.600 8.300 ;
    END
  END vdd
  PIN gnd
    DIRECTION INOUT ;
    USE GROUND ;
    SHAPE ABUTMENT ;
    PORT
      LAYER metal1 ;
        RECT 0.000 -0.300 13.600 0.300 ;
        RECT 3.600 0.300 4.000 1.000 ;
        RECT 9.200 0.300 9.600 1.000 ;
        RECT 11.600 0.300 12.000 1.000 ;
    END
  END gnd
  OBS
    LAYER metal1 ;
      RECT 1.200 0.600 1.600 1.400 ;
      RECT 2.000 0.600 2.400 1.000 ;
      RECT 2.800 0.600 3.200 1.000 ;
      RECT 4.400 0.600 4.800 1.400 ;
      RECT 5.200 0.600 5.600 0.700 ;
      RECT 6.000 0.600 6.400 1.600 ;
      RECT 6.800 0.600 7.200 1.000 ;
      RECT 8.400 0.600 8.800 0.700 ;
      RECT 10.000 0.600 10.400 1.000 ;
      RECT 5.100 0.700 5.600 1.300 ;
      RECT 8.400 0.700 8.900 1.000 ;
      RECT 2.100 1.000 2.500 1.400 ;
      RECT 2.800 1.000 3.100 1.600 ;
      RECT 6.800 1.000 7.100 1.200 ;
      RECT 8.600 1.000 8.900 1.700 ;
      RECT 10.000 1.000 10.300 1.300 ;
      RECT 6.700 1.200 7.100 1.600 ;
      RECT 5.100 1.300 5.500 1.600 ;
      RECT 9.600 1.300 10.300 1.600 ;
      RECT 2.800 1.600 3.600 2.000 ;
      RECT 9.600 1.600 9.900 2.500 ;
      RECT 8.600 1.700 9.200 2.000 ;
      RECT 5.800 1.900 7.600 2.200 ;
      RECT 2.800 2.000 3.200 2.100 ;
      RECT 8.900 2.000 9.200 5.000 ;
      RECT 5.800 2.200 6.200 2.300 ;
      RECT 7.200 2.200 7.600 2.300 ;
      RECT 9.500 2.500 9.900 2.900 ;
      RECT 9.600 2.900 9.900 5.700 ;
      RECT 1.200 3.000 1.600 3.400 ;
      RECT 1.200 3.400 1.500 4.900 ;
      RECT 11.300 3.400 11.700 3.800 ;
      RECT 11.300 3.800 11.600 4.200 ;
      RECT 5.300 4.100 7.800 4.400 ;
      RECT 11.300 4.200 11.700 4.600 ;
      RECT 5.300 4.400 5.700 4.500 ;
      RECT 7.400 4.400 7.800 4.500 ;
      RECT 11.300 4.600 11.600 5.900 ;
      RECT 6.000 4.700 6.400 5.100 ;
      RECT 1.200 4.900 3.700 5.200 ;
      RECT 8.900 5.000 9.300 5.400 ;
      RECT 6.000 5.100 6.300 5.800 ;
      RECT 1.200 5.200 1.500 7.000 ;
      RECT 3.300 5.200 3.700 5.300 ;
      RECT 2.900 5.600 3.600 5.900 ;
      RECT 6.800 5.600 7.200 6.000 ;
      RECT 8.500 5.700 10.200 6.000 ;
      RECT 4.700 5.800 6.400 5.900 ;
      RECT 2.100 5.900 3.600 6.000 ;
      RECT 4.700 5.900 6.500 6.100 ;
      RECT 11.300 5.900 11.700 6.300 ;
      RECT 2.100 6.000 3.200 6.200 ;
      RECT 6.800 6.000 7.100 7.000 ;
      RECT 8.500 6.000 8.900 6.100 ;
      RECT 9.900 6.000 10.200 7.000 ;
      RECT 4.700 6.100 5.100 6.200 ;
      RECT 6.100 6.100 6.500 6.300 ;
      RECT 2.100 6.200 2.500 6.300 ;
      RECT 2.900 6.200 3.200 7.000 ;
      RECT 4.300 6.500 4.700 6.800 ;
      RECT 2.000 6.600 2.400 7.400 ;
      RECT 5.100 6.600 5.500 7.000 ;
      RECT 6.000 6.600 6.400 7.400 ;
      RECT 8.500 6.600 8.900 7.000 ;
      RECT 4.300 6.800 4.800 7.300 ;
      RECT 1.200 7.000 1.600 7.400 ;
      RECT 2.800 7.000 3.200 7.400 ;
      RECT 5.100 7.000 5.600 7.300 ;
      RECT 6.800 7.000 7.200 7.400 ;
      RECT 8.400 7.000 8.800 7.400 ;
      RECT 9.900 7.000 10.400 7.300 ;
      RECT 4.400 7.300 4.800 7.400 ;
      RECT 5.200 7.300 5.600 7.400 ;
      RECT 10.000 7.300 10.400 7.400 ;
      RECT 0.300 0.400 0.500 0.600 ;
      RECT 0.300 7.400 0.500 7.600 ;
      RECT 1.100 0.400 1.300 0.600 ;
      RECT 1.100 7.400 1.300 7.600 ;
      RECT 3.500 3.400 3.700 3.600 ;
      RECT 3.500 4.400 3.700 4.600 ;
      RECT 3.500 5.400 3.700 5.600 ;
      RECT 3.500 6.400 3.700 6.600 ;
      RECT 4.300 2.400 4.500 2.600 ;
      RECT 4.300 3.400 4.500 3.600 ;
      RECT 4.300 4.400 4.500 4.600 ;
      RECT 4.300 5.400 4.500 5.600 ;
      RECT 4.300 6.400 4.500 6.600 ;
      RECT 5.100 2.400 5.300 2.600 ;
      RECT 5.100 3.400 5.300 3.600 ;
      RECT 5.900 2.400 6.100 2.600 ;
      RECT 5.900 3.400 6.100 3.600 ;
      RECT 6.700 2.400 6.900 2.600 ;
      RECT 6.700 3.400 6.900 3.600 ;
      RECT 7.500 0.400 7.700 0.600 ;
      RECT 7.500 1.400 7.700 1.600 ;
      RECT 7.500 2.400 7.700 2.600 ;
      RECT 7.500 5.400 7.700 5.600 ;
      RECT 7.500 6.400 7.700 6.600 ;
      RECT 7.500 7.400 7.700 7.600 ;
      RECT 8.300 0.400 8.500 0.600 ;
      RECT 8.300 1.400 8.500 1.600 ;
      RECT 8.300 2.400 8.500 2.600 ;
      RECT 8.300 5.400 8.500 5.600 ;
      RECT 8.300 6.400 8.500 6.600 ;
      RECT 8.300 7.400 8.500 7.600 ;
      RECT 10.700 0.400 10.900 0.600 ;
      RECT 10.700 1.400 10.900 1.600 ;
      RECT 10.700 2.400 10.900 2.600 ;
      RECT 10.700 7.400 10.900 7.600 ;
      RECT 11.500 1.400 11.700 1.600 ;
      RECT 11.500 2.400 11.700 2.600 ;
      RECT 11.500 3.400 11.700 3.600 ;
      RECT 11.500 6.400 11.700 6.600 ;
      RECT 12.300 0.400 12.500 0.600 ;
      RECT 12.300 7.400 12.500 7.600 ;
      RECT 13.100 0.400 13.300 0.600 ;
      RECT 13.100 6.400 13.300 6.600 ;
      RECT 13.100 7.400 13.300 7.600 ;
    LAYER metal2 ;
      RECT 2.100 0.900 4.700 1.000 ;
      RECT 1.200 1.000 1.600 1.400 ;
      RECT 2.000 1.000 4.800 1.200 ;
      RECT 2.000 1.200 2.500 1.400 ;
      RECT 4.400 1.200 4.800 1.400 ;
      RECT 5.100 1.200 5.500 1.600 ;
      RECT 6.000 1.200 6.400 1.600 ;
      RECT 6.700 1.200 7.100 1.600 ;
      RECT 1.200 1.400 1.500 3.000 ;
      RECT 2.000 1.400 2.300 6.500 ;
      RECT 3.200 1.600 3.600 2.000 ;
      RECT 5.100 1.600 5.400 4.100 ;
      RECT 6.000 1.600 6.300 6.600 ;
      RECT 6.800 1.600 7.100 4.200 ;
      RECT 3.200 2.000 3.500 5.600 ;
      RECT 1.200 3.000 1.600 3.400 ;
      RECT 5.100 4.100 5.700 4.500 ;
      RECT 6.800 4.200 11.700 4.500 ;
      RECT 5.100 4.500 5.400 6.600 ;
      RECT 6.800 4.500 7.100 5.600 ;
      RECT 11.300 4.500 11.700 4.600 ;
      RECT 8.600 5.000 9.300 5.400 ;
      RECT 8.600 5.400 8.900 6.600 ;
      RECT 3.200 5.600 3.600 6.000 ;
      RECT 6.800 5.600 7.200 6.000 ;
      RECT 2.000 6.500 4.700 6.800 ;
      RECT 5.100 6.600 5.500 7.000 ;
      RECT 6.000 6.600 8.900 6.900 ;
      RECT 2.000 6.800 2.400 7.000 ;
      RECT 4.300 6.800 4.700 6.900 ;
      RECT 6.000 6.900 6.400 7.000 ;
      RECT 8.500 6.900 8.900 7.000 ;
  END
END pl_fa

MACRO pl_fb4
  CLASS CORE ;
  FOREIGN pl_fb4 0.000 0.000 ;
  ORIGIN 0.000 0.000 ;
  SIZE 14.400 BY 8.000 ;
  SYMMETRY X Y ;
  SITE plcore ;
  PIN A
    DIRECTION INPUT ;
    PORT
      LAYER metal1 ;
        RECT 12.200 4.300 12.600 4.700 ;
        RECT 8.400 2.000 8.800 2.400 ;
        RECT 8.400 2.400 8.700 4.300 ;
        RECT 8.400 4.300 9.400 4.600 ;
        RECT 11.000 4.300 12.600 4.600 ;
        RECT 8.400 4.600 8.700 5.600 ;
        RECT 9.000 4.600 9.400 4.700 ;
        RECT 11.000 4.600 11.400 4.700 ;
        RECT 12.200 4.600 12.600 4.700 ;
        RECT 8.400 5.600 8.800 6.000 ;
      LAYER metal2 ;
        RECT 9.000 4.300 11.400 4.600 ;
        RECT 9.000 4.600 9.400 4.700 ;
        RECT 11.000 4.600 11.400 4.700 ;
    END
  END A
  PIN B
    DIRECTION INPUT ;
    PORT
      LAYER metal1 ;
        RECT 11.400 3.300 11.800 3.700 ;
        RECT 11.000 3.300 11.800 3.700 ;
    END
  END B
  PIN C0
    DIRECTION INPUT ;
    PORT
      LAYER metal1 ;
        RECT 2.600 3.300 3.000 3.700 ;
        RECT 2.600 0.600 3.000 1.000 ;
        RECT 2.700 1.000 3.000 3.300 ;
        RECT 2.600 3.300 3.000 3.700 ;
        RECT 2.700 3.700 3.000 4.500 ;
        RECT 2.700 4.500 3.100 4.900 ;
        RECT 2.700 6.500 3.100 6.900 ;
        RECT 2.600 6.900 3.000 7.400 ;
      LAYER metal2 ;
        RECT 2.700 4.500 3.100 4.900 ;
        RECT 2.700 4.900 3.000 6.500 ;
        RECT 2.700 6.500 3.100 6.900 ;
    END
  END C0
  PIN C1
    DIRECTION INPUT ;
    PORT
      LAYER metal1 ;
        RECT 0.200 3.300 0.600 3.700 ;
        RECT 0.200 0.600 0.600 1.000 ;
        RECT 0.200 1.000 0.500 3.300 ;
        RECT 0.200 3.300 0.600 3.700 ;
        RECT 0.200 3.700 0.500 6.900 ;
        RECT 0.200 6.900 0.600 7.400 ;
    END
  END C1
  PIN C2
    DIRECTION INPUT ;
    PORT
      LAYER metal1 ;
        RECT 3.400 3.300 3.800 3.700 ;
        RECT 3.400 0.600 3.800 1.000 ;
        RECT 3.400 1.000 3.700 3.300 ;
        RECT 3.400 3.300 3.800 3.700 ;
        RECT 3.400 3.700 3.700 4.500 ;
        RECT 3.400 4.500 3.800 4.900 ;
        RECT 3.400 6.500 3.800 7.400 ;
      LAYER metal2 ;
        RECT 3.400 4.500 3.800 4.900 ;
        RECT 3.400 4.900 3.700 6.500 ;
        RECT 3.400 6.500 3.800 6.900 ;
    END
  END C2
  PIN C3
    DIRECTION INPUT ;
    PORT
      LAYER metal1 ;
        RECT 5.800 1.300 6.200 1.700 ;
        RECT 5.800 0.600 6.200 1.000 ;
        RECT 5.800 1.000 6.100 1.300 ;
        RECT 5.800 1.300 6.200 1.700 ;
        RECT 5.800 1.700 6.100 2.000 ;
        RECT 5.800 2.000 6.200 2.400 ;
        RECT 5.800 3.400 6.200 3.800 ;
        RECT 5.900 3.800 6.200 6.900 ;
        RECT 5.800 6.900 6.200 7.400 ;
      LAYER metal2 ;
        RECT 5.800 2.000 6.200 2.400 ;
        RECT 5.800 2.400 6.100 3.400 ;
        RECT 5.800 3.400 6.200 3.800 ;
    END
  END C3
  PIN P
    DIRECTION OUTPUT ;
    PORT
      LAYER metal1 ;
        RECT 13.800 3.300 14.200 3.700 ;
        RECT 13.800 0.600 14.200 1.400 ;
        RECT 13.800 2.600 14.200 3.000 ;
        RECT 13.800 3.000 14.100 3.300 ;
        RECT 13.800 3.300 14.200 3.700 ;
        RECT 13.800 3.700 14.100 6.400 ;
        RECT 13.800 6.400 14.200 7.400 ;
      LAYER metal2 ;
        RECT 13.800 1.000 14.200 1.400 ;
        RECT 13.800 1.400 14.100 2.600 ;
        RECT 13.800 2.600 14.200 3.000 ;
    END
  END P
  PIN vdd
    DIRECTION INOUT ;
    USE POWER ;
    SHAPE ABUTMENT ;
    PORT
      LAYER metal1 ;
        RECT 10.600 6.900 11.000 7.700 ;
        RECT 13.000 6.900 13.400 7.700 ;
        RECT 0.000 7.700 14.400 8.300 ;
    END
  END vdd
  PIN gnd
    DIRECTION INOUT ;
    USE GROUND ;
    SHAPE ABUTMENT ;
    PORT
      LAYER metal1 ;
        RECT 0.000 -0.300 14.400 0.300 ;
        RECT 10.600 0.300 11.000 1.000 ;
        RECT 13.000 0.300 13.400 1.000 ;
    END
  END gnd
  OBS
    LAYER metal1 ;
      RECT 1.400 0.600 1.800 1.000 ;
      RECT 4.600 0.600 5.000 1.000 ;
      RECT 6.600 0.600 7.000 0.700 ;
      RECT 7.400 0.600 8.200 1.000 ;
      RECT 9.000 0.600 9.400 1.000 ;
      RECT 9.800 0.600 10.200 0.700 ;
      RECT 11.400 0.600 11.800 1.000 ;
      RECT 12.200 0.600 12.600 1.000 ;
      RECT 6.500 0.700 7.000 1.000 ;
      RECT 9.700 0.700 10.200 1.000 ;
      RECT 1.400 1.000 1.700 5.200 ;
      RECT 4.700 1.000 5.000 2.000 ;
      RECT 6.500 1.000 6.800 2.000 ;
      RECT 9.100 1.000 9.400 3.600 ;
      RECT 9.700 1.000 10.000 1.300 ;
      RECT 11.400 1.000 11.700 2.700 ;
      RECT 12.200 1.000 12.500 1.700 ;
      RECT 4.000 1.300 4.400 1.700 ;
      RECT 7.800 1.300 8.600 1.700 ;
      RECT 9.700 1.300 10.100 1.700 ;
      RECT 4.000 1.700 4.300 2.700 ;
      RECT 9.700 1.700 10.000 6.200 ;
      RECT 12.200 1.700 13.800 2.000 ;
      RECT 4.700 2.000 5.100 2.400 ;
      RECT 6.500 2.000 6.900 2.300 ;
      RECT 7.400 2.000 7.800 2.400 ;
      RECT 13.400 2.000 13.800 2.100 ;
      RECT 6.600 2.300 6.900 5.200 ;
      RECT 7.400 2.400 7.700 5.600 ;
      RECT 4.000 2.700 6.300 3.000 ;
      RECT 10.300 2.700 11.700 3.000 ;
      RECT 4.700 3.000 5.000 5.500 ;
      RECT 5.900 3.000 6.300 3.100 ;
      RECT 10.300 3.000 10.700 3.100 ;
      RECT 10.400 3.100 10.700 6.300 ;
      RECT 9.000 3.600 9.400 4.000 ;
      RECT 1.400 5.200 4.400 5.500 ;
      RECT 6.500 5.200 6.900 5.600 ;
      RECT 1.000 5.500 1.700 5.800 ;
      RECT 4.000 5.500 4.400 5.600 ;
      RECT 4.700 5.500 5.300 5.800 ;
      RECT 6.500 5.600 6.800 6.900 ;
      RECT 7.400 5.600 8.100 6.000 ;
      RECT 11.000 5.600 12.800 5.900 ;
      RECT 1.000 5.800 1.400 5.900 ;
      RECT 4.700 5.800 5.600 5.900 ;
      RECT 2.100 5.900 5.600 6.200 ;
      RECT 11.000 5.900 11.400 6.000 ;
      RECT 12.400 5.900 12.800 6.000 ;
      RECT 13.100 5.900 13.500 6.300 ;
      RECT 7.400 6.000 7.700 6.900 ;
      RECT 0.800 6.200 2.400 6.500 ;
      RECT 9.600 6.200 10.000 6.600 ;
      RECT 10.400 6.300 11.700 6.600 ;
      RECT 12.300 6.300 13.400 6.600 ;
      RECT 0.800 6.500 1.200 6.600 ;
      RECT 4.700 6.500 5.100 6.900 ;
      RECT 8.500 6.500 8.900 6.900 ;
      RECT 9.700 6.600 10.000 6.900 ;
      RECT 11.400 6.600 11.700 6.900 ;
      RECT 12.300 6.600 12.600 6.900 ;
      RECT 1.000 6.900 1.800 7.300 ;
      RECT 4.600 6.900 5.000 7.400 ;
      RECT 6.500 6.900 7.000 7.200 ;
      RECT 7.400 6.900 8.200 7.200 ;
      RECT 8.500 6.900 9.400 7.200 ;
      RECT 9.700 6.900 10.200 7.200 ;
      RECT 11.400 6.900 11.800 7.400 ;
      RECT 12.200 6.900 12.600 7.400 ;
      RECT 6.600 7.200 7.000 7.400 ;
      RECT 7.800 7.200 8.200 7.400 ;
      RECT 9.000 7.200 9.400 7.400 ;
      RECT 9.800 7.200 10.200 7.400 ;
      RECT 1.400 7.300 1.800 7.400 ;
      RECT 0.300 0.400 0.500 0.600 ;
      RECT 0.300 7.400 0.500 7.600 ;
      RECT 2.700 0.400 2.900 0.600 ;
      RECT 2.700 7.400 2.900 7.600 ;
      RECT 3.500 0.400 3.700 0.600 ;
      RECT 3.500 7.400 3.700 7.600 ;
      RECT 5.900 0.400 6.100 0.600 ;
      RECT 5.900 2.400 6.100 2.600 ;
      RECT 5.900 7.400 6.100 7.600 ;
      RECT 9.100 2.400 9.300 2.600 ;
      RECT 9.100 5.400 9.300 5.600 ;
      RECT 10.700 3.400 10.900 3.600 ;
      RECT 10.700 4.400 10.900 4.600 ;
      RECT 13.900 0.400 14.100 0.600 ;
      RECT 13.900 1.400 14.100 1.600 ;
      RECT 13.900 2.400 14.100 2.600 ;
      RECT 13.900 7.400 14.100 7.600 ;
    LAYER metal2 ;
      RECT 7.400 0.600 7.800 1.000 ;
      RECT 7.400 1.000 7.700 2.000 ;
      RECT 8.200 1.300 10.100 1.600 ;
      RECT 8.200 1.600 8.600 1.700 ;
      RECT 9.700 1.600 10.100 1.700 ;
      RECT 4.700 2.000 5.100 2.400 ;
      RECT 7.400 2.000 7.800 2.400 ;
      RECT 4.700 2.400 5.000 6.500 ;
      RECT 7.100 3.600 9.400 3.900 ;
      RECT 7.100 3.900 7.400 6.500 ;
      RECT 9.000 3.900 9.400 4.000 ;
      RECT 1.000 5.500 1.400 5.900 ;
      RECT 7.700 5.600 11.400 5.900 ;
      RECT 1.000 5.900 1.300 6.900 ;
      RECT 7.700 5.900 8.100 6.000 ;
      RECT 11.000 5.900 11.400 6.000 ;
      RECT 4.700 6.500 8.900 6.800 ;
      RECT 4.700 6.800 5.100 6.900 ;
      RECT 8.500 6.800 8.900 6.900 ;
      RECT 1.000 6.900 1.400 7.300 ;
      RECT 11.500 4.400 11.700 4.600 ;
  END
END pl_fb4

MACRO pl_cs
  CLASS CORE ;
  FOREIGN pl_cs 0.000 0.000 ;
  ORIGIN 0.000 0.000 ;
  SIZE 13.600 BY 8.000 ;
  SYMMETRY X Y ;
  SITE plcore ;
  PIN P
    DIRECTION INPUT ;
    PORT
      LAYER metal1 ;
        RECT 1.800 3.300 2.200 3.700 ;
        RECT 1.900 1.300 2.300 1.700 ;
        RECT 1.900 1.700 2.200 3.300 ;
        RECT 5.300 2.900 5.700 3.300 ;
        RECT 1.800 3.300 2.200 3.700 ;
        RECT 5.300 3.300 5.600 3.700 ;
        RECT 1.900 3.700 5.600 4.000 ;
        RECT 1.900 4.000 2.200 4.700 ;
        RECT 3.900 4.000 4.300 4.100 ;
        RECT 1.900 4.700 2.300 5.100 ;
    END
  END P
  PIN A
    DIRECTION INPUT ;
    PORT
      LAYER metal1 ;
        RECT 0.200 3.300 0.600 3.700 ;
        RECT 0.400 0.600 0.800 1.000 ;
        RECT 0.400 1.000 0.700 3.300 ;
        RECT 0.200 3.300 0.700 3.700 ;
        RECT 0.400 3.700 0.700 6.800 ;
        RECT 0.400 6.800 0.800 7.400 ;
    END
  END A
  PIN CI
    DIRECTION INPUT ;
    PORT
      LAYER metal1 ;
        RECT 2.600 2.300 3.000 2.700 ;
        RECT 2.400 0.600 2.800 0.700 ;
        RECT 2.400 0.700 3.000 1.000 ;
        RECT 2.700 1.000 3.000 2.300 ;
        RECT 2.600 2.300 3.000 2.600 ;
        RECT 2.500 2.600 3.000 2.900 ;
        RECT 2.500 2.900 4.900 3.200 ;
        RECT 2.500 3.200 2.900 3.300 ;
        RECT 4.500 3.200 4.900 3.300 ;
        RECT 2.400 6.400 2.900 6.800 ;
        RECT 2.400 6.800 2.800 7.400 ;
      LAYER metal2 ;
        RECT 2.500 2.900 2.900 3.300 ;
        RECT 2.500 3.300 2.800 6.400 ;
        RECT 2.500 6.400 2.900 6.800 ;
    END
  END CI
  PIN K
    DIRECTION INPUT ;
    PORT
      LAYER metal1 ;
        RECT 9.800 3.300 10.200 3.700 ;
        RECT 9.400 3.300 10.200 3.700 ;
    END
  END K
  PIN CO
    DIRECTION OUTPUT ;
    PORT
      LAYER metal1 ;
        RECT 13.000 4.300 13.400 4.700 ;
        RECT 11.200 0.600 11.600 1.800 ;
        RECT 12.200 4.300 13.400 4.600 ;
        RECT 12.200 4.600 12.600 4.700 ;
        RECT 13.000 4.600 13.400 4.700 ;
        RECT 11.200 5.800 11.600 7.400 ;
      LAYER metal2 ;
        RECT 11.200 1.400 11.600 1.800 ;
        RECT 11.200 1.800 11.500 4.300 ;
        RECT 11.200 4.300 12.600 4.600 ;
        RECT 11.200 4.600 11.500 5.800 ;
        RECT 12.200 4.600 12.600 4.700 ;
        RECT 11.200 5.800 11.600 6.200 ;
    END
  END CO
  PIN Y
    DIRECTION OUTPUT ;
    PORT
      LAYER metal1 ;
        RECT 13.000 2.300 13.400 2.700 ;
        RECT 12.800 0.600 13.200 1.400 ;
        RECT 12.900 1.400 13.200 2.300 ;
        RECT 12.900 2.300 13.400 3.200 ;
        RECT 13.000 3.200 13.400 3.300 ;
        RECT 13.000 5.000 13.400 5.400 ;
        RECT 13.000 5.400 13.300 6.200 ;
        RECT 12.800 6.200 13.300 6.500 ;
        RECT 12.800 6.500 13.200 7.400 ;
    END
  END Y
  PIN vdd
    DIRECTION INOUT ;
    USE POWER ;
    SHAPE ABUTMENT ;
    PORT
      LAYER metal1 ;
        RECT 12.000 6.200 12.400 7.700 ;
        RECT 5.200 6.800 5.600 7.700 ;
        RECT 9.600 6.800 10.000 7.700 ;
        RECT 0.000 7.700 13.600 8.300 ;
    END
  END vdd
  PIN gnd
    DIRECTION INOUT ;
    USE GROUND ;
    SHAPE ABUTMENT ;
    PORT
      LAYER metal1 ;
        RECT 0.000 -0.300 13.600 0.300 ;
        RECT 5.200 0.300 5.600 1.000 ;
        RECT 9.600 0.300 10.000 1.000 ;
        RECT 12.000 0.300 12.400 1.400 ;
    END
  END gnd
  OBS
    LAYER metal1 ;
      RECT 1.400 0.600 1.800 0.700 ;
      RECT 3.400 0.600 3.800 0.700 ;
      RECT 4.400 0.600 4.800 1.000 ;
      RECT 6.000 0.600 6.400 1.000 ;
      RECT 7.000 0.600 7.400 1.000 ;
      RECT 8.000 0.600 8.400 0.700 ;
      RECT 8.800 0.600 9.200 1.000 ;
      RECT 10.400 0.600 10.800 1.000 ;
      RECT 1.200 0.700 1.800 1.000 ;
      RECT 3.400 0.700 4.000 1.000 ;
      RECT 7.700 0.700 8.400 1.000 ;
      RECT 1.200 1.000 1.500 5.400 ;
      RECT 3.700 1.000 4.100 1.400 ;
      RECT 4.400 1.000 4.700 1.600 ;
      RECT 6.000 1.000 6.300 2.300 ;
      RECT 7.100 1.000 7.400 4.500 ;
      RECT 7.700 1.000 8.100 1.400 ;
      RECT 8.800 1.000 9.100 1.300 ;
      RECT 10.400 1.000 10.700 2.100 ;
      RECT 8.500 1.300 9.100 1.700 ;
      RECT 4.400 1.600 4.800 2.000 ;
      RECT 8.800 1.700 9.100 2.500 ;
      RECT 3.300 1.800 3.700 2.100 ;
      RECT 3.300 2.100 4.000 2.300 ;
      RECT 10.400 2.100 12.000 2.400 ;
      RECT 3.300 2.300 6.300 2.600 ;
      RECT 11.600 2.400 12.000 2.500 ;
      RECT 8.800 2.500 9.200 2.900 ;
      RECT 11.600 2.500 11.900 5.100 ;
      RECT 6.000 2.600 6.300 6.800 ;
      RECT 7.100 4.500 11.300 4.800 ;
      RECT 7.100 4.800 7.700 5.000 ;
      RECT 10.900 4.800 11.300 4.900 ;
      RECT 7.300 5.000 7.700 5.100 ;
      RECT 8.200 5.100 10.400 5.400 ;
      RECT 11.600 5.100 12.000 5.500 ;
      RECT 1.200 5.400 5.700 5.700 ;
      RECT 6.600 5.400 8.500 5.700 ;
      RECT 10.000 5.400 10.400 5.500 ;
      RECT 1.200 5.700 1.500 6.800 ;
      RECT 5.300 5.700 5.700 5.800 ;
      RECT 6.600 5.700 7.000 5.800 ;
      RECT 8.800 5.800 9.200 6.200 ;
      RECT 10.400 5.800 10.900 6.200 ;
      RECT 8.800 6.200 9.100 6.800 ;
      RECT 10.400 6.200 10.700 6.800 ;
      RECT 3.700 6.300 4.100 6.700 ;
      RECT 4.400 6.300 4.800 7.400 ;
      RECT 7.100 6.400 7.500 6.800 ;
      RECT 8.000 6.400 8.400 7.400 ;
      RECT 3.700 6.700 4.000 6.800 ;
      RECT 1.200 6.800 1.800 7.100 ;
      RECT 3.400 6.800 4.000 7.100 ;
      RECT 6.000 6.800 6.400 7.400 ;
      RECT 7.000 6.800 7.400 7.400 ;
      RECT 8.800 6.800 9.200 7.400 ;
      RECT 10.400 6.800 10.800 7.400 ;
      RECT 1.400 7.100 1.800 7.400 ;
      RECT 3.400 7.100 3.800 7.400 ;
      RECT 0.300 0.400 0.500 0.600 ;
      RECT 0.300 7.400 0.500 7.600 ;
      RECT 1.100 0.400 1.300 0.600 ;
      RECT 1.100 6.400 1.300 6.600 ;
      RECT 1.100 7.400 1.300 7.600 ;
      RECT 1.900 0.400 2.100 0.600 ;
      RECT 1.900 5.400 2.100 5.600 ;
      RECT 1.900 6.400 2.100 6.600 ;
      RECT 1.900 7.400 2.100 7.600 ;
      RECT 2.700 0.400 2.900 0.600 ;
      RECT 2.700 3.400 2.900 3.600 ;
      RECT 2.700 7.400 2.900 7.600 ;
      RECT 3.500 2.400 3.700 2.600 ;
      RECT 3.500 3.400 3.700 3.600 ;
      RECT 3.500 4.400 3.700 4.600 ;
      RECT 4.300 2.400 4.500 2.600 ;
      RECT 4.300 3.400 4.500 3.600 ;
      RECT 4.300 4.400 4.500 4.600 ;
      RECT 5.100 2.400 5.300 2.600 ;
      RECT 5.100 3.400 5.300 3.600 ;
      RECT 5.900 2.400 6.100 2.600 ;
      RECT 5.900 3.400 6.100 3.600 ;
      RECT 9.100 3.400 9.300 3.600 ;
      RECT 10.700 0.400 10.900 0.600 ;
      RECT 10.700 1.400 10.900 1.600 ;
      RECT 10.700 5.400 10.900 5.600 ;
      RECT 10.700 6.400 10.900 6.600 ;
      RECT 10.700 7.400 10.900 7.600 ;
      RECT 11.500 0.400 11.700 0.600 ;
      RECT 11.500 5.400 11.700 5.600 ;
      RECT 11.500 7.400 11.700 7.600 ;
      RECT 12.300 1.400 12.500 1.600 ;
      RECT 13.100 0.400 13.300 0.600 ;
      RECT 13.100 3.400 13.300 3.600 ;
      RECT 13.100 7.400 13.300 7.600 ;
    LAYER metal2 ;
      RECT 3.700 1.000 8.300 1.300 ;
      RECT 3.700 1.300 4.100 1.400 ;
      RECT 7.700 1.300 8.300 1.400 ;
      RECT 3.700 1.400 4.000 6.300 ;
      RECT 8.000 1.400 8.300 6.400 ;
      RECT 4.400 1.600 4.800 2.000 ;
      RECT 4.400 2.000 4.700 6.300 ;
      RECT 7.300 4.700 7.700 5.100 ;
      RECT 7.300 5.100 7.600 6.400 ;
      RECT 5.300 5.400 7.000 5.700 ;
      RECT 5.300 5.700 5.700 5.800 ;
      RECT 6.600 5.700 7.000 5.800 ;
      RECT 3.700 6.300 4.100 6.700 ;
      RECT 4.400 6.300 4.800 6.700 ;
      RECT 7.100 6.400 7.600 6.700 ;
      RECT 8.000 6.400 8.400 6.800 ;
      RECT 7.100 6.700 7.500 6.800 ;
      RECT 10.700 1.400 10.900 1.600 ;
      RECT 10.700 2.400 10.900 2.600 ;
      RECT 10.700 3.400 10.900 3.600 ;
      RECT 10.700 4.400 10.900 4.600 ;
      RECT 10.700 5.400 10.900 5.600 ;
      RECT 10.700 6.400 10.900 6.600 ;
      RECT 11.500 2.400 11.700 2.600 ;
      RECT 11.500 3.400 11.700 3.600 ;
      RECT 11.500 5.400 11.700 5.600 ;
      RECT 11.500 6.400 11.700 6.600 ;
  END
END pl_cs

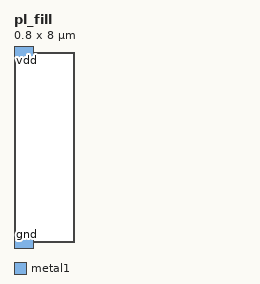
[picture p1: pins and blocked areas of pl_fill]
MACRO pl_fill
  CLASS CORE ;
  FOREIGN pl_fill 0.000 0.000 ;
  ORIGIN 0.000 0.000 ;
  SIZE 0.800 BY 8.000 ;
  SYMMETRY X Y ;
  SITE plcore ;
  PIN vdd
    DIRECTION INOUT ;
    USE POWER ;
    SHAPE ABUTMENT ;
    PORT
      LAYER metal1 ;
        RECT 0.000 7.700 0.800 8.300 ;
    END
  END vdd
  PIN gnd
    DIRECTION INOUT ;
    USE GROUND ;
    SHAPE ABUTMENT ;
    PORT
      LAYER metal1 ;
        RECT 0.000 -0.300 0.800 0.300 ;
    END
  END gnd
END pl_fill

END LIBRARY
